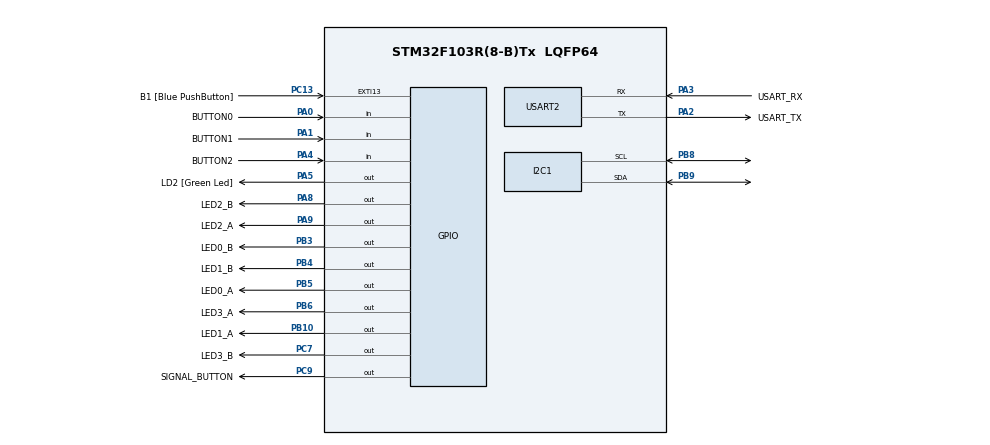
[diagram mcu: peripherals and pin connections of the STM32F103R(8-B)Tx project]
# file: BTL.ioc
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Mcu.Family=STM32F1
Mcu.Name=STM32F103R(8-B)Tx
Mcu.Package=LQFP64
NVIC.EXTI15_10_IRQn=true\:0\:0\:false\:false\:true\:true\:true\:true
NVIC.I2C1_ER_IRQn=true\:0\:0\:false\:false\:true\:true\:true\:true
NVIC.I2C1_EV_IRQn=true\:0\:0\:false\:false\:true\:true\:true\:true
NVIC.PriorityGroup=NVIC_PRIORITYGROUP_4
NVIC.TIM2_IRQn=true\:0\:0\:false\:false\:true\:true\:true\:true
PA0-WKUP.GPIO_Label=BUTTON0
PA0-WKUP.GPIO_PuPd=GPIO_PULLUP
PA0-WKUP.Signal=GPIO_Input
PA1.GPIO_Label=BUTTON1
PA1.GPIO_PuPd=GPIO_PULLUP
PA1.Signal=GPIO_Input
PA13.GPIO_Label=TMS
PA13.Mode=Serial_Wire
PA13.Signal=SYS_JTMS-SWDIO
PA14.GPIO_Label=TCK
PA14.Mode=Serial_Wire
PA14.Signal=SYS_JTCK-SWCLK
PA2.GPIO_Label=USART_TX
PA2.GPIO_Mode=GPIO_MODE_AF_PP
PA2.GPIO_PuPd=GPIO_NOPULL
PA2.GPIO_Speed=GPIO_SPEED_FREQ_LOW
PA2.Mode=Asynchronous
PA2.Signal=USART2_TX
PA3.GPIO_Label=USART_RX
PA3.GPIO_Mode=GPIO_MODE_AF_PP
PA3.GPIO_PuPd=GPIO_NOPULL
PA3.GPIO_Speed=GPIO_SPEED_FREQ_LOW
PA3.Mode=Asynchronous
PA3.Signal=USART2_RX
PA4.GPIO_Label=BUTTON2
PA4.GPIO_PuPd=GPIO_PULLUP
PA4.Signal=GPIO_Input
PA5.GPIO_Label=LD2 [Green Led]
PA5.GPIO_ModeDefaultOutputPP=GPIO_MODE_OUTPUT_PP
PA5.GPIO_PuPd=GPIO_NOPULL
PA5.GPIO_Speed=GPIO_SPEED_FREQ_LOW
PA5.Signal=GPIO_Output
PA8.GPIO_Label=LED2_B
PA8.Signal=GPIO_Output
PA9.GPIO_Label=LED2_A
PA9.Signal=GPIO_Output
PB10.GPIO_Label=LED1_A
PB10.Signal=GPIO_Output
PB3.GPIO_Label=LED0_B
PB3.Signal=GPIO_Output
PB4.GPIO_Label=LED1_B
PB4.Signal=GPIO_Output
PB5.GPIO_Label=LED0_A
PB5.Signal=GPIO_Output
PB6.GPIO_Label=LED3_A
PB6.Signal=GPIO_Output
PB8.Mode=I2C
PB8.Signal=I2C1_SCL
PB9.Mode=I2C
PB9.Signal=I2C1_SDA
PC13-TAMPER-RTC.GPIO_Label=B1 [Blue PushButton]
PC13-TAMPER-RTC.GPIO_PuPd=GPIO_NOPULL
PC13-TAMPER-RTC.Signal=GPXTI13
PC14-OSC32_IN.Mode=LSE-External-Oscillator
PC14-OSC32_IN.Signal=RCC_OSC32_IN
PC15-OSC32_OUT.Mode=LSE-External-Oscillator
PC15-OSC32_OUT.Signal=RCC_OSC32_OUT
PC7.GPIO_Label=LED3_B
PC7.Signal=GPIO_Output
PC9.GPIO_Label=SIGNAL_BUTTON
PC9.Signal=GPIO_Output
PD0-OSC_IN.Mode=HSE-External-Clock-Source
PD0-OSC_IN.Signal=RCC_OSC_IN
PD1-OSC_OUT.Mode=HSE-External-Clock-Source
PD1-OSC_OUT.Signal=RCC_OSC_OUT
ProjectManager.HeapSize=0x200
ProjectManager.StackSize=0x400
ProjectManager.TargetToolchain=STM32CubeIDE
RCC.AHBFreq_Value=8000000
RCC.APB1CLKDivider=RCC_HCLK_DIV2
RCC.APB1Freq_Value=4000000
RCC.APB1TimFreq_Value=8000000
RCC.APB2Freq_Value=8000000
RCC.APB2TimFreq_Value=8000000
RCC.HCLKFreq_Value=8000000
RCC.RTCClockSelection=RCC_RTCCLKSOURCE_LSE
RCC.SYSCLKFreq_VALUE=8000000
RCC.SYSCLKSource=RCC_SYSCLKSOURCE_PLLCLK
RCC.USBFreq_Value=8000000
TIM2.Period=9
TIM2.Prescaler=7999
USART2.VirtualMode=VM_ASYNC
VP_TIM2_VS_ClockSourceINT.Mode=Internal
board=NUCLEO-F103RB

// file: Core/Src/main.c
/* USER CODE BEGIN Header */
/**
  ******************************************************************************
  * @file           : main.c
  * @brief          : Main program body
  ******************************************************************************
  * @attention
  *
  * Copyright (c) 2024 STMicroelectronics.
  * All rights reserved.
  *
  * This software is licensed under terms that can be found in the LICENSE file
  * in the root directory of this software component.
  * If no LICENSE file comes with this software, it is provided AS-IS.
  *
  ******************************************************************************
  */
/* USER CODE END Header */
#include "main.h"

/* USER CODE BEGIN Includes */
#include "global.h"
/* USER CODE END Includes */

I2C_HandleTypeDef hi2c1;

TIM_HandleTypeDef htim2;

UART_HandleTypeDef huart2;

void SystemClock_Config(void);
static void MX_GPIO_Init(void);
static void MX_TIM2_Init(void);
static void MX_I2C1_Init(void);
static void MX_USART2_UART_Init(void);

int main(void)
{

  /* MCU Configuration--------------------------------------------------------*/

  /* Reset of all peripherals, Initializes the Flash interface and the Systick. */
  HAL_Init();

  /* Configure the system clock */
  SystemClock_Config();

  /* Initialize all configured peripherals */
  MX_GPIO_Init();
  MX_TIM2_Init();
  MX_I2C1_Init();
  MX_USART2_UART_Init();
  /* USER CODE BEGIN 2 */
  HAL_TIM_Base_Start_IT(&htim2);
    status = INIT;
    lcd_init();
  /* USER CODE END 2 */

  /* Infinite loop */
  /* USER CODE BEGIN WHILE */
  lcd_init();
  while (1)
  {
    /* USER CODE END WHILE */

    /* USER CODE BEGIN 3 */
	fsm_auto_run();
	fsm_modify_run();
	fsm_manual_run();
  }
  /* USER CODE END 3 */
}

void SystemClock_Config(void)
{
  RCC_OscInitTypeDef RCC_OscInitStruct = {0};
  RCC_ClkInitTypeDef RCC_ClkInitStruct = {0};

  /** Initializes the RCC Oscillators according to the specified parameters
  * in the RCC_OscInitTypeDef structure.
  */
  RCC_OscInitStruct.OscillatorType = RCC_OSCILLATORTYPE_HSI;
  RCC_OscInitStruct.HSIState = RCC_HSI_ON;
  RCC_OscInitStruct.HSICalibrationValue = RCC_HSICALIBRATION_DEFAULT;
  RCC_OscInitStruct.PLL.PLLState = RCC_PLL_NONE;
  if (HAL_RCC_OscConfig(&RCC_OscInitStruct) != HAL_OK)
  {
    Error_Handler();
  }

  /** Initializes the CPU, AHB and APB buses clocks
  */
  RCC_ClkInitStruct.ClockType = RCC_CLOCKTYPE_HCLK|RCC_CLOCKTYPE_SYSCLK
                              |RCC_CLOCKTYPE_PCLK1|RCC_CLOCKTYPE_PCLK2;
  RCC_ClkInitStruct.SYSCLKSource = RCC_SYSCLKSOURCE_HSI;
  RCC_ClkInitStruct.AHBCLKDivider = RCC_SYSCLK_DIV1;
  RCC_ClkInitStruct.APB1CLKDivider = RCC_HCLK_DIV1;
  RCC_ClkInitStruct.APB2CLKDivider = RCC_HCLK_DIV1;

  if (HAL_RCC_ClockConfig(&RCC_ClkInitStruct, FLASH_LATENCY_0) != HAL_OK)
  {
    Error_Handler();
  }
}

static void MX_I2C1_Init(void)
{

  hi2c1.Instance = I2C1;
  hi2c1.Init.ClockSpeed = 100000;
  hi2c1.Init.DutyCycle = I2C_DUTYCYCLE_2;
  hi2c1.Init.OwnAddress1 = 0;
  hi2c1.Init.AddressingMode = I2C_ADDRESSINGMODE_7BIT;
  hi2c1.Init.DualAddressMode = I2C_DUALADDRESS_DISABLE;
  hi2c1.Init.OwnAddress2 = 0;
  hi2c1.Init.GeneralCallMode = I2C_GENERALCALL_DISABLE;
  hi2c1.Init.NoStretchMode = I2C_NOSTRETCH_DISABLE;
  if (HAL_I2C_Init(&hi2c1) != HAL_OK)
  {
    Error_Handler();
  }

}

static void MX_TIM2_Init(void)
{

  TIM_ClockConfigTypeDef sClockSourceConfig = {0};
  TIM_MasterConfigTypeDef sMasterConfig = {0};

  htim2.Instance = TIM2;
  htim2.Init.Prescaler = 7999;
  htim2.Init.CounterMode = TIM_COUNTERMODE_UP;
  htim2.Init.Period = 9;
  htim2.Init.ClockDivision = TIM_CLOCKDIVISION_DIV1;
  htim2.Init.AutoReloadPreload = TIM_AUTORELOAD_PRELOAD_DISABLE;
  if (HAL_TIM_Base_Init(&htim2) != HAL_OK)
  {
    Error_Handler();
  }
  sClockSourceConfig.ClockSource = TIM_CLOCKSOURCE_INTERNAL;
  if (HAL_TIM_ConfigClockSource(&htim2, &sClockSourceConfig) != HAL_OK)
  {
    Error_Handler();
  }
  sMasterConfig.MasterOutputTrigger = TIM_TRGO_RESET;
  sMasterConfig.MasterSlaveMode = TIM_MASTERSLAVEMODE_DISABLE;
  if (HAL_TIMEx_MasterConfigSynchronization(&htim2, &sMasterConfig) != HAL_OK)
  {
    Error_Handler();
  }

}

static void MX_USART2_UART_Init(void)
{

  huart2.Instance = USART2;
  huart2.Init.BaudRate = 115200;
  huart2.Init.WordLength = UART_WORDLENGTH_8B;
  huart2.Init.StopBits = UART_STOPBITS_1;
  huart2.Init.Parity = UART_PARITY_NONE;
  huart2.Init.Mode = UART_MODE_TX_RX;
  huart2.Init.HwFlowCtl = UART_HWCONTROL_NONE;
  huart2.Init.OverSampling = UART_OVERSAMPLING_16;
  if (HAL_UART_Init(&huart2) != HAL_OK)
  {
    Error_Handler();
  }

}

static void MX_GPIO_Init(void)
{
  GPIO_InitTypeDef GPIO_InitStruct = {0};

  /* GPIO Ports Clock Enable */
  __HAL_RCC_GPIOC_CLK_ENABLE();
  __HAL_RCC_GPIOA_CLK_ENABLE();
  __HAL_RCC_GPIOB_CLK_ENABLE();

  /*Configure GPIO pin Output Level */
  HAL_GPIO_WritePin(GPIOA, LD2_Pin|LED2_B_Pin|LED2_A_Pin, GPIO_PIN_RESET);

  /*Configure GPIO pin Output Level */
  HAL_GPIO_WritePin(GPIOB, LED1_A_Pin|LED0_B_Pin|LED1_B_Pin|LED0_A_Pin
                          |LED3_A_Pin, GPIO_PIN_RESET);

  /*Configure GPIO pin Output Level */
  HAL_GPIO_WritePin(GPIOC, LED3_B_Pin|SIGNAL_BUTTON_Pin, GPIO_PIN_RESET);

  /*Configure GPIO pin : B1_Pin */
  GPIO_InitStruct.Pin = B1_Pin;
  GPIO_InitStruct.Mode = GPIO_MODE_IT_RISING;
  GPIO_InitStruct.Pull = GPIO_NOPULL;
  HAL_GPIO_Init(B1_GPIO_Port, &GPIO_InitStruct);

  /*Configure GPIO pins : BUTTON0_Pin BUTTON1_Pin BUTTON2_Pin */
  GPIO_InitStruct.Pin = BUTTON0_Pin|BUTTON1_Pin|BUTTON2_Pin;
  GPIO_InitStruct.Mode = GPIO_MODE_INPUT;
  GPIO_InitStruct.Pull = GPIO_PULLUP;
  HAL_GPIO_Init(GPIOA, &GPIO_InitStruct);

  /*Configure GPIO pins : LD2_Pin LED2_B_Pin LED2_A_Pin */
  GPIO_InitStruct.Pin = LD2_Pin|LED2_B_Pin|LED2_A_Pin;
  GPIO_InitStruct.Mode = GPIO_MODE_OUTPUT_PP;
  GPIO_InitStruct.Pull = GPIO_NOPULL;
  GPIO_InitStruct.Speed = GPIO_SPEED_FREQ_LOW;
  HAL_GPIO_Init(GPIOA, &GPIO_InitStruct);

  /*Configure GPIO pins : LED1_A_Pin LED0_B_Pin LED1_B_Pin LED0_A_Pin
                           LED3_A_Pin */
  GPIO_InitStruct.Pin = LED1_A_Pin|LED0_B_Pin|LED1_B_Pin|LED0_A_Pin
                          |LED3_A_Pin;
  GPIO_InitStruct.Mode = GPIO_MODE_OUTPUT_PP;
  GPIO_InitStruct.Pull = GPIO_NOPULL;
  GPIO_InitStruct.Speed = GPIO_SPEED_FREQ_LOW;
  HAL_GPIO_Init(GPIOB, &GPIO_InitStruct);

  /*Configure GPIO pins : LED3_B_Pin SIGNAL_BUTTON_Pin */
  GPIO_InitStruct.Pin = LED3_B_Pin|SIGNAL_BUTTON_Pin;
  GPIO_InitStruct.Mode = GPIO_MODE_OUTPUT_PP;
  GPIO_InitStruct.Pull = GPIO_NOPULL;
  GPIO_InitStruct.Speed = GPIO_SPEED_FREQ_LOW;
  HAL_GPIO_Init(GPIOC, &GPIO_InitStruct);

  /* EXTI interrupt init*/
  HAL_NVIC_SetPriority(EXTI15_10_IRQn, 0, 0);
  HAL_NVIC_EnableIRQ(EXTI15_10_IRQn);

}

/* USER CODE BEGIN 4 */
void HAL_TIM_PeriodElapsedCallback(TIM_HandleTypeDef *htim){
	timerRun();
	getKeyInput();
}
/* USER CODE END 4 */

void Error_Handler(void)
{
  __disable_irq();
  while (1)
  {
  }
}
